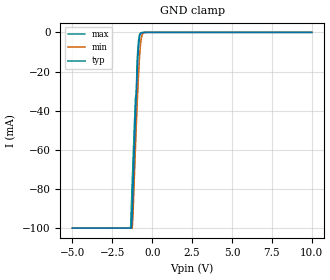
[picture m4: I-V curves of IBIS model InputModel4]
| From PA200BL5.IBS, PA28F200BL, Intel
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|***************************Input Model 4****************************
[Model]   InputModel4
Model_type   Input
|   Model for OE#
Vinl = 0.8V
Vinh = 2.0V
|Variable   typ   min   max
C_comp   4.91p   NA   6.50p
[Voltage Range]   5.0V   4.5V   5.5V
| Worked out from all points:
|   GND clamp passes 1 mA (typ) near -0.75 V on its own axis
[GND_clamp]
|Voltage   I(typ)   I(min)   I(max)
-5V       -99.85mA   -99.85mA   -99.85mA
-1.4V     -99.85mA   -99.85mA   -99.85mA
-1.35V    -99.85mA   -99.85mA   -98.82mA
-1.3V     -99.85mA   -99.85mA   -87.43mA
-1.2V     -79.43mA   -92.36mA   -64.95mA
-1.05V    -42.94mA   -58.78mA   -33.33mA
-1V       -31.95mA   -48.24mA   -32mA
-950mV    -21.89mA   -38.16mA   -15.39mA
-850mV    -6.927mA   -20.54mA   -3.764mA
-750mV    -1.006mA   -7.653mA   -469.5uA
-500mV    -17.68uA   -102.4uA   0A
10V       0A         0A         0A
[Power_clamp]
| Input buffer circuits of this product do not intrinisically
| require a [Power_clamp] defintion.  This zero current
| [Power_clamp] table is provided for the compatibility with
| some IBIS parsers.
|Voltage   I(typ)   I(min)   I(max)
-5V       0A         0A         0A
0V        0A         0A         0A
5V        0A         0A         0A
10V       0A         0A         0A
